VERSION 5.7 ;
  NOWIREEXTENSIONATPIN ON ;
  DIVIDERCHAR "/" ;
  BUSBITCHARS "[]" ;
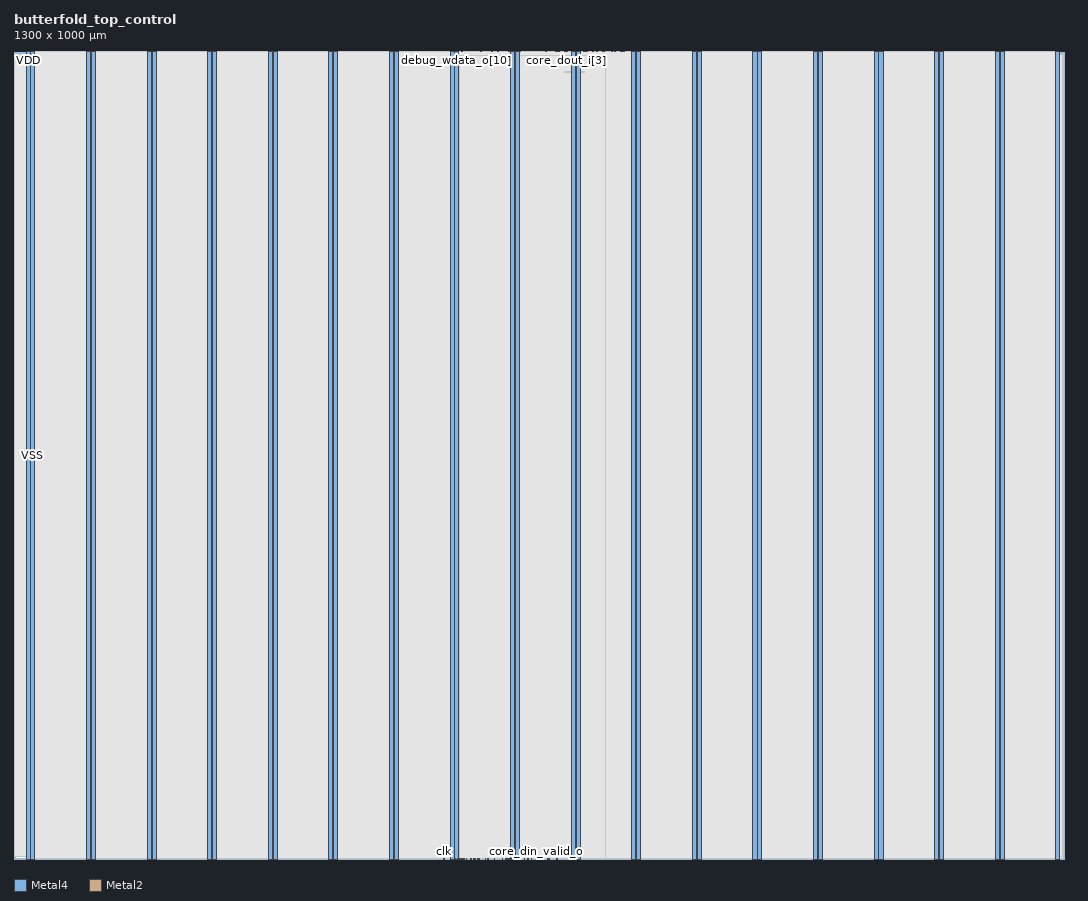
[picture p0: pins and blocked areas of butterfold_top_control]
MACRO butterfold_top_control
  CLASS BLOCK ;
  FOREIGN butterfold_top_control ;
  ORIGIN 0.000 0.000 ;
  SIZE 1300.000 BY 1000.000 ;
  PIN VDD
    DIRECTION INOUT ;
    USE POWER ;
    PORT
      LAYER Metal4 ;
        RECT 14.940 0.000 19.940 1000.000 ;
    END
    PORT
      LAYER Metal4 ;
        RECT 89.940 0.000 94.940 1000.000 ;
    END
    PORT
      LAYER Metal4 ;
        RECT 164.940 0.000 169.940 1000.000 ;
    END
    PORT
      LAYER Metal4 ;
        RECT 239.940 0.000 244.940 1000.000 ;
    END
    PORT
      LAYER Metal4 ;
        RECT 314.940 0.000 319.940 1000.000 ;
    END
    PORT
      LAYER Metal4 ;
        RECT 389.940 0.000 394.940 1000.000 ;
    END
    PORT
      LAYER Metal4 ;
        RECT 464.940 0.000 469.940 1000.000 ;
    END
    PORT
      LAYER Metal4 ;
        RECT 539.940 0.000 544.940 1000.000 ;
    END
    PORT
      LAYER Metal4 ;
        RECT 614.940 0.000 619.940 1000.000 ;
    END
    PORT
      LAYER Metal4 ;
        RECT 689.940 0.000 694.940 1000.000 ;
    END
    PORT
      LAYER Metal4 ;
        RECT 764.940 0.000 769.940 1000.000 ;
    END
    PORT
      LAYER Metal4 ;
        RECT 839.940 0.000 844.940 1000.000 ;
    END
    PORT
      LAYER Metal4 ;
        RECT 914.940 0.000 919.940 1000.000 ;
    END
    PORT
      LAYER Metal4 ;
        RECT 989.940 0.000 994.940 1000.000 ;
    END
    PORT
      LAYER Metal4 ;
        RECT 1064.940 0.000 1069.940 1000.000 ;
    END
    PORT
      LAYER Metal4 ;
        RECT 1139.940 0.000 1144.940 1000.000 ;
    END
    PORT
      LAYER Metal4 ;
        RECT 1214.940 0.000 1219.940 1000.000 ;
    END
    PORT
      LAYER Metal4 ;
        RECT 1289.940 0.000 1294.940 1000.000 ;
    END
  END VDD
  PIN VSS
    DIRECTION INOUT ;
    USE GROUND ;
    PORT
      LAYER Metal4 ;
        RECT 20.940 0.000 25.940 1000.000 ;
    END
    PORT
      LAYER Metal4 ;
        RECT 95.940 0.000 100.940 1000.000 ;
    END
    PORT
      LAYER Metal4 ;
        RECT 170.940 0.000 175.940 1000.000 ;
    END
    PORT
      LAYER Metal4 ;
        RECT 245.940 0.000 250.940 1000.000 ;
    END
    PORT
      LAYER Metal4 ;
        RECT 320.940 0.000 325.940 1000.000 ;
    END
    PORT
      LAYER Metal4 ;
        RECT 395.940 0.000 400.940 1000.000 ;
    END
    PORT
      LAYER Metal4 ;
        RECT 470.940 0.000 475.940 1000.000 ;
    END
    PORT
      LAYER Metal4 ;
        RECT 545.940 0.000 550.940 1000.000 ;
    END
    PORT
      LAYER Metal4 ;
        RECT 620.940 0.000 625.940 1000.000 ;
    END
    PORT
      LAYER Metal4 ;
        RECT 695.940 0.000 700.940 1000.000 ;
    END
    PORT
      LAYER Metal4 ;
        RECT 770.940 0.000 775.940 1000.000 ;
    END
    PORT
      LAYER Metal4 ;
        RECT 845.940 0.000 850.940 1000.000 ;
    END
    PORT
      LAYER Metal4 ;
        RECT 920.940 0.000 925.940 1000.000 ;
    END
    PORT
      LAYER Metal4 ;
        RECT 995.940 0.000 1000.940 1000.000 ;
    END
    PORT
      LAYER Metal4 ;
        RECT 1070.940 0.000 1075.940 1000.000 ;
    END
    PORT
      LAYER Metal4 ;
        RECT 1145.940 0.000 1150.940 1000.000 ;
    END
    PORT
      LAYER Metal4 ;
        RECT 1220.940 0.000 1225.940 1000.000 ;
    END
  END VSS
  PIN clk
    DIRECTION INPUT ;
    USE SIGNAL ;
    ANTENNAGATEAREA 4.738000 ;
    ANTENNADIFFAREA 0.410400 ;
    PORT
      LAYER Metal2 ;
        RECT 532.000 0.000 532.560 0.560 ;
    END
  END clk
  PIN core_din_ready_i
    DIRECTION INPUT ;
    USE SIGNAL ;
    ANTENNAGATEAREA 0.396000 ;
    ANTENNADIFFAREA 0.410400 ;
    PORT
      LAYER Metal2 ;
        RECT 633.920 999.440 634.480 1000.000 ;
    END
  END core_din_ready_i
  PIN core_din_valid_o
    DIRECTION OUTPUT ;
    USE SIGNAL ;
    ANTENNADIFFAREA 0.897600 ;
    PORT
      LAYER Metal2 ;
        RECT 646.240 0.000 646.800 0.560 ;
    END
  END core_din_valid_o
  PIN core_dout_i[0]
    DIRECTION INPUT ;
    USE SIGNAL ;
    ANTENNAGATEAREA 0.396000 ;
    ANTENNADIFFAREA 0.410400 ;
    PORT
      LAYER Metal2 ;
        RECT 695.520 999.440 696.080 1000.000 ;
    END
  END core_dout_i[0]
  PIN core_dout_i[1]
    DIRECTION INPUT ;
    USE SIGNAL ;
    ANTENNAGATEAREA 0.396000 ;
    ANTENNADIFFAREA 0.410400 ;
    PORT
      LAYER Metal2 ;
        RECT 715.680 999.440 716.240 1000.000 ;
    END
  END core_dout_i[1]
  PIN core_dout_i[2]
    DIRECTION INPUT ;
    USE SIGNAL ;
    ANTENNAGATEAREA 0.396000 ;
    ANTENNADIFFAREA 0.410400 ;
    PORT
      LAYER Metal2 ;
        RECT 722.400 999.440 722.960 1000.000 ;
    END
  END core_dout_i[2]
  PIN core_dout_i[3]
    DIRECTION INPUT ;
    USE SIGNAL ;
    ANTENNAGATEAREA 0.396000 ;
    ANTENNADIFFAREA 0.410400 ;
    PORT
      LAYER Metal2 ;
        RECT 684.320 999.440 684.880 1000.000 ;
    END
  END core_dout_i[3]
  PIN core_dout_i[4]
    DIRECTION INPUT ;
    USE SIGNAL ;
    ANTENNAGATEAREA 0.396000 ;
    ANTENNADIFFAREA 0.410400 ;
    PORT
      LAYER Metal2 ;
        RECT 670.880 999.440 671.440 1000.000 ;
    END
  END core_dout_i[4]
  PIN core_dout_i[5]
    DIRECTION INPUT ;
    USE SIGNAL ;
    ANTENNAGATEAREA 0.396000 ;
    ANTENNADIFFAREA 0.410400 ;
    PORT
      LAYER Metal2 ;
        RECT 710.080 999.440 710.640 1000.000 ;
    END
  END core_dout_i[5]
  PIN core_dout_i[6]
    DIRECTION INPUT ;
    USE SIGNAL ;
    ANTENNAGATEAREA 0.396000 ;
    ANTENNADIFFAREA 0.410400 ;
    PORT
      LAYER Metal2 ;
        RECT 679.840 999.440 680.400 1000.000 ;
    END
  END core_dout_i[6]
  PIN core_dout_i[7]
    DIRECTION INPUT ;
    USE SIGNAL ;
    ANTENNAGATEAREA 0.396000 ;
    ANTENNADIFFAREA 0.410400 ;
    PORT
      LAYER Metal2 ;
        RECT 724.640 999.440 725.200 1000.000 ;
    END
  END core_dout_i[7]
  PIN core_dout_valid_i
    DIRECTION INPUT ;
    USE SIGNAL ;
    ANTENNAGATEAREA 0.396000 ;
    ANTENNADIFFAREA 0.410400 ;
    PORT
      LAYER Metal2 ;
        RECT 705.600 999.440 706.160 1000.000 ;
    END
  END core_dout_valid_i
  PIN core_ofdm_active
    DIRECTION OUTPUT ;
    USE SIGNAL ;
    ANTENNADIFFAREA 0.897600 ;
    PORT
      LAYER Metal2 ;
        RECT 660.800 0.000 661.360 0.560 ;
    END
  END core_ofdm_active
  PIN core_result_ready_o
    DIRECTION OUTPUT ;
    USE SIGNAL ;
    ANTENNADIFFAREA 0.897600 ;
    PORT
      LAYER Metal2 ;
        RECT 610.400 0.000 610.960 0.560 ;
    END
  END core_result_ready_o
  PIN core_rx_complete
    DIRECTION OUTPUT ;
    USE SIGNAL ;
    ANTENNADIFFAREA 0.897600 ;
    PORT
      LAYER Metal2 ;
        RECT 614.880 0.000 615.440 0.560 ;
    END
  END core_rx_complete
  PIN core_rx_selected_complete
    DIRECTION OUTPUT ;
    USE SIGNAL ;
    ANTENNADIFFAREA 0.897600 ;
    PORT
      LAYER Metal2 ;
        RECT 617.120 0.000 617.680 0.560 ;
    END
  END core_rx_selected_complete
  PIN core_tx_complete
    DIRECTION OUTPUT ;
    USE SIGNAL ;
    ANTENNADIFFAREA 0.897600 ;
    PORT
      LAYER Metal2 ;
        RECT 611.520 0.000 612.080 0.560 ;
    END
  END core_tx_complete
  PIN debug_addr_o[0]
    DIRECTION OUTPUT ;
    USE SIGNAL ;
    ANTENNADIFFAREA 0.897600 ;
    PORT
      LAYER Metal2 ;
        RECT 604.800 0.000 605.360 0.560 ;
    END
  END debug_addr_o[0]
  PIN debug_addr_o[1]
    DIRECTION OUTPUT ;
    USE SIGNAL ;
    ANTENNADIFFAREA 0.897600 ;
    PORT
      LAYER Metal2 ;
        RECT 586.880 0.000 587.440 0.560 ;
    END
  END debug_addr_o[1]
  PIN debug_addr_o[2]
    DIRECTION OUTPUT ;
    USE SIGNAL ;
    ANTENNADIFFAREA 0.897600 ;
    PORT
      LAYER Metal2 ;
        RECT 551.040 0.000 551.600 0.560 ;
    END
  END debug_addr_o[2]
  PIN debug_addr_o[3]
    DIRECTION OUTPUT ;
    USE SIGNAL ;
    ANTENNADIFFAREA 0.897600 ;
    PORT
      LAYER Metal2 ;
        RECT 560.000 0.000 560.560 0.560 ;
    END
  END debug_addr_o[3]
  PIN debug_addr_o[4]
    DIRECTION OUTPUT ;
    USE SIGNAL ;
    ANTENNADIFFAREA 0.897600 ;
    PORT
      LAYER Metal2 ;
        RECT 548.800 0.000 549.360 0.560 ;
    END
  END debug_addr_o[4]
  PIN debug_addr_o[5]
    DIRECTION OUTPUT ;
    USE SIGNAL ;
    ANTENNADIFFAREA 0.897600 ;
    PORT
      LAYER Metal2 ;
        RECT 573.440 0.000 574.000 0.560 ;
    END
  END debug_addr_o[5]
  PIN debug_addr_o[6]
    DIRECTION OUTPUT ;
    USE SIGNAL ;
    ANTENNADIFFAREA 0.897600 ;
    PORT
      LAYER Metal2 ;
        RECT 570.080 0.000 570.640 0.560 ;
    END
  END debug_addr_o[6]
  PIN debug_addr_o[7]
    DIRECTION OUTPUT ;
    USE SIGNAL ;
    ANTENNADIFFAREA 0.897600 ;
    PORT
      LAYER Metal2 ;
        RECT 594.720 0.000 595.280 0.560 ;
    END
  END debug_addr_o[7]
  PIN debug_mode_o
    DIRECTION OUTPUT ;
    USE SIGNAL ;
    ANTENNADIFFAREA 0.897600 ;
    PORT
      LAYER Metal2 ;
        RECT 683.200 999.440 683.760 1000.000 ;
    END
  END debug_mode_o
  PIN debug_rdata_i[0]
    DIRECTION INPUT ;
    USE SIGNAL ;
    ANTENNAGATEAREA 0.396000 ;
    ANTENNADIFFAREA 0.410400 ;
    PORT
      LAYER Metal2 ;
        RECT 707.840 999.440 708.400 1000.000 ;
    END
  END debug_rdata_i[0]
  PIN debug_rdata_i[10]
    DIRECTION INPUT ;
    USE SIGNAL ;
    ANTENNAGATEAREA 0.396000 ;
    ANTENNADIFFAREA 0.410400 ;
    PORT
      LAYER Metal2 ;
        RECT 750.400 999.440 750.960 1000.000 ;
    END
  END debug_rdata_i[10]
  PIN debug_rdata_i[11]
    DIRECTION INPUT ;
    USE SIGNAL ;
    ANTENNAGATEAREA 0.396000 ;
    ANTENNADIFFAREA 0.410400 ;
    PORT
      LAYER Metal2 ;
        RECT 656.320 999.440 656.880 1000.000 ;
    END
  END debug_rdata_i[11]
  PIN debug_rdata_i[12]
    DIRECTION INPUT ;
    USE SIGNAL ;
    ANTENNAGATEAREA 0.396000 ;
    ANTENNADIFFAREA 0.410400 ;
    PORT
      LAYER Metal2 ;
        RECT 657.440 999.440 658.000 1000.000 ;
    END
  END debug_rdata_i[12]
  PIN debug_rdata_i[13]
    DIRECTION INPUT ;
    USE SIGNAL ;
    ANTENNAGATEAREA 0.396000 ;
    ANTENNADIFFAREA 0.410400 ;
    PORT
      LAYER Metal2 ;
        RECT 658.560 999.440 659.120 1000.000 ;
    END
  END debug_rdata_i[13]
  PIN debug_rdata_i[14]
    DIRECTION INPUT ;
    USE SIGNAL ;
    ANTENNAGATEAREA 0.396000 ;
    ANTENNADIFFAREA 0.410400 ;
    PORT
      LAYER Metal2 ;
        RECT 743.680 999.440 744.240 1000.000 ;
    END
  END debug_rdata_i[14]
  PIN debug_rdata_i[15]
    DIRECTION INPUT ;
    USE SIGNAL ;
    ANTENNAGATEAREA 0.396000 ;
    ANTENNADIFFAREA 0.410400 ;
    PORT
      LAYER Metal2 ;
        RECT 751.520 999.440 752.080 1000.000 ;
    END
  END debug_rdata_i[15]
  PIN debug_rdata_i[1]
    DIRECTION INPUT ;
    USE SIGNAL ;
    ANTENNAGATEAREA 0.396000 ;
    ANTENNADIFFAREA 0.410400 ;
    PORT
      LAYER Metal2 ;
        RECT 739.200 999.440 739.760 1000.000 ;
    END
  END debug_rdata_i[1]
  PIN debug_rdata_i[2]
    DIRECTION INPUT ;
    USE SIGNAL ;
    ANTENNAGATEAREA 0.396000 ;
    ANTENNADIFFAREA 0.410400 ;
    PORT
      LAYER Metal2 ;
        RECT 752.640 999.440 753.200 1000.000 ;
    END
  END debug_rdata_i[2]
  PIN debug_rdata_i[3]
    DIRECTION INPUT ;
    USE SIGNAL ;
    ANTENNAGATEAREA 0.396000 ;
    ANTENNADIFFAREA 0.410400 ;
    PORT
      LAYER Metal2 ;
        RECT 667.520 999.440 668.080 1000.000 ;
    END
  END debug_rdata_i[3]
  PIN debug_rdata_i[4]
    DIRECTION INPUT ;
    USE SIGNAL ;
    ANTENNAGATEAREA 0.396000 ;
    ANTENNADIFFAREA 0.410400 ;
    PORT
      LAYER Metal2 ;
        RECT 673.120 999.440 673.680 1000.000 ;
    END
  END debug_rdata_i[4]
  PIN debug_rdata_i[5]
    DIRECTION INPUT ;
    USE SIGNAL ;
    ANTENNAGATEAREA 0.396000 ;
    ANTENNADIFFAREA 0.410400 ;
    PORT
      LAYER Metal2 ;
        RECT 740.320 999.440 740.880 1000.000 ;
    END
  END debug_rdata_i[5]
  PIN debug_rdata_i[6]
    DIRECTION INPUT ;
    USE SIGNAL ;
    ANTENNAGATEAREA 0.396000 ;
    ANTENNADIFFAREA 0.410400 ;
    PORT
      LAYER Metal2 ;
        RECT 754.880 999.440 755.440 1000.000 ;
    END
  END debug_rdata_i[6]
  PIN debug_rdata_i[7]
    DIRECTION INPUT ;
    USE SIGNAL ;
    ANTENNAGATEAREA 0.396000 ;
    ANTENNADIFFAREA 0.410400 ;
    PORT
      LAYER Metal2 ;
        RECT 723.520 999.440 724.080 1000.000 ;
    END
  END debug_rdata_i[7]
  PIN debug_rdata_i[8]
    DIRECTION INPUT ;
    USE SIGNAL ;
    ANTENNAGATEAREA 0.396000 ;
    ANTENNADIFFAREA 0.410400 ;
    PORT
      LAYER Metal2 ;
        RECT 692.160 999.440 692.720 1000.000 ;
    END
  END debug_rdata_i[8]
  PIN debug_rdata_i[9]
    DIRECTION INPUT ;
    USE SIGNAL ;
    ANTENNAGATEAREA 0.396000 ;
    ANTENNADIFFAREA 0.410400 ;
    PORT
      LAYER Metal2 ;
        RECT 706.720 999.440 707.280 1000.000 ;
    END
  END debug_rdata_i[9]
  PIN debug_ready_i
    DIRECTION INPUT ;
    USE SIGNAL ;
    ANTENNAGATEAREA 0.396000 ;
    ANTENNADIFFAREA 0.410400 ;
    PORT
      LAYER Metal2 ;
        RECT 686.560 999.440 687.120 1000.000 ;
    END
  END debug_ready_i
  PIN debug_req_o
    DIRECTION OUTPUT ;
    USE SIGNAL ;
    ANTENNADIFFAREA 0.897600 ;
    PORT
      LAYER Metal2 ;
        RECT 680.960 999.440 681.520 1000.000 ;
    END
  END debug_req_o
  PIN debug_rvalid_i
    DIRECTION INPUT ;
    USE SIGNAL ;
    ANTENNAGATEAREA 0.396000 ;
    ANTENNADIFFAREA 0.410400 ;
    PORT
      LAYER Metal2 ;
        RECT 682.080 999.440 682.640 1000.000 ;
    END
  END debug_rvalid_i
  PIN debug_wdata_o[0]
    DIRECTION OUTPUT ;
    USE SIGNAL ;
    ANTENNADIFFAREA 0.897600 ;
    PORT
      LAYER Metal2 ;
        RECT 626.080 999.440 626.640 1000.000 ;
    END
  END debug_wdata_o[0]
  PIN debug_wdata_o[10]
    DIRECTION OUTPUT ;
    USE SIGNAL ;
    ANTENNADIFFAREA 0.897600 ;
    PORT
      LAYER Metal2 ;
        RECT 547.680 999.440 548.240 1000.000 ;
    END
  END debug_wdata_o[10]
  PIN debug_wdata_o[11]
    DIRECTION OUTPUT ;
    USE SIGNAL ;
    ANTENNADIFFAREA 0.897600 ;
    PORT
      LAYER Metal2 ;
        RECT 551.040 999.440 551.600 1000.000 ;
    END
  END debug_wdata_o[11]
  PIN debug_wdata_o[12]
    DIRECTION OUTPUT ;
    USE SIGNAL ;
    ANTENNADIFFAREA 0.897600 ;
    PORT
      LAYER Metal2 ;
        RECT 549.920 999.440 550.480 1000.000 ;
    END
  END debug_wdata_o[12]
  PIN debug_wdata_o[13]
    DIRECTION OUTPUT ;
    USE SIGNAL ;
    ANTENNADIFFAREA 0.897600 ;
    PORT
      LAYER Metal2 ;
        RECT 574.560 999.440 575.120 1000.000 ;
    END
  END debug_wdata_o[13]
  PIN debug_wdata_o[14]
    DIRECTION OUTPUT ;
    USE SIGNAL ;
    ANTENNADIFFAREA 0.897600 ;
    PORT
      LAYER Metal2 ;
        RECT 593.600 999.440 594.160 1000.000 ;
    END
  END debug_wdata_o[14]
  PIN debug_wdata_o[15]
    DIRECTION OUTPUT ;
    USE SIGNAL ;
    ANTENNADIFFAREA 0.897600 ;
    PORT
      LAYER Metal2 ;
        RECT 591.360 999.440 591.920 1000.000 ;
    END
  END debug_wdata_o[15]
  PIN debug_wdata_o[1]
    DIRECTION OUTPUT ;
    USE SIGNAL ;
    ANTENNADIFFAREA 0.897600 ;
    PORT
      LAYER Metal2 ;
        RECT 617.120 999.440 617.680 1000.000 ;
    END
  END debug_wdata_o[1]
  PIN debug_wdata_o[2]
    DIRECTION OUTPUT ;
    USE SIGNAL ;
    ANTENNADIFFAREA 0.897600 ;
    PORT
      LAYER Metal2 ;
        RECT 549.920 0.000 550.480 0.560 ;
    END
  END debug_wdata_o[2]
  PIN debug_wdata_o[3]
    DIRECTION OUTPUT ;
    USE SIGNAL ;
    ANTENNADIFFAREA 0.897600 ;
    PORT
      LAYER Metal2 ;
        RECT 577.920 999.440 578.480 1000.000 ;
    END
  END debug_wdata_o[3]
  PIN debug_wdata_o[4]
    DIRECTION OUTPUT ;
    USE SIGNAL ;
    ANTENNADIFFAREA 0.897600 ;
    PORT
      LAYER Metal2 ;
        RECT 554.400 999.440 554.960 1000.000 ;
    END
  END debug_wdata_o[4]
  PIN debug_wdata_o[5]
    DIRECTION OUTPUT ;
    USE SIGNAL ;
    ANTENNADIFFAREA 0.897600 ;
    PORT
      LAYER Metal2 ;
        RECT 572.320 999.440 572.880 1000.000 ;
    END
  END debug_wdata_o[5]
  PIN debug_wdata_o[6]
    DIRECTION OUTPUT ;
    USE SIGNAL ;
    ANTENNADIFFAREA 0.897600 ;
    PORT
      LAYER Metal2 ;
        RECT 571.200 0.000 571.760 0.560 ;
    END
  END debug_wdata_o[6]
  PIN debug_wdata_o[7]
    DIRECTION OUTPUT ;
    USE SIGNAL ;
    ANTENNADIFFAREA 0.897600 ;
    PORT
      LAYER Metal2 ;
        RECT 612.640 999.440 613.200 1000.000 ;
    END
  END debug_wdata_o[7]
  PIN debug_wdata_o[8]
    DIRECTION OUTPUT ;
    USE SIGNAL ;
    ANTENNADIFFAREA 0.897600 ;
    PORT
      LAYER Metal2 ;
        RECT 616.000 999.440 616.560 1000.000 ;
    END
  END debug_wdata_o[8]
  PIN debug_wdata_o[9]
    DIRECTION OUTPUT ;
    USE SIGNAL ;
    ANTENNADIFFAREA 0.897600 ;
    PORT
      LAYER Metal2 ;
        RECT 599.200 999.440 599.760 1000.000 ;
    END
  END debug_wdata_o[9]
  PIN debug_write_o
    DIRECTION OUTPUT ;
    USE SIGNAL ;
    ANTENNADIFFAREA 0.897600 ;
    PORT
      LAYER Metal2 ;
        RECT 672.000 999.440 672.560 1000.000 ;
    END
  END debug_write_o
  PIN din[0]
    DIRECTION INPUT ;
    USE SIGNAL ;
    ANTENNAGATEAREA 0.396000 ;
    ANTENNADIFFAREA 0.410400 ;
    PORT
      LAYER Metal2 ;
        RECT 651.840 0.000 652.400 0.560 ;
    END
  END din[0]
  PIN din[1]
    DIRECTION INPUT ;
    USE SIGNAL ;
    ANTENNAGATEAREA 0.396000 ;
    ANTENNADIFFAREA 0.410400 ;
    PORT
      LAYER Metal2 ;
        RECT 621.600 0.000 622.160 0.560 ;
    END
  END din[1]
  PIN din[2]
    DIRECTION INPUT ;
    USE SIGNAL ;
    ANTENNAGATEAREA 0.726000 ;
    ANTENNADIFFAREA 0.410400 ;
    PORT
      LAYER Metal2 ;
        RECT 553.280 0.000 553.840 0.560 ;
    END
  END din[2]
  PIN din[3]
    DIRECTION INPUT ;
    USE SIGNAL ;
    ANTENNAGATEAREA 0.396000 ;
    ANTENNADIFFAREA 0.410400 ;
    PORT
      LAYER Metal2 ;
        RECT 636.160 0.000 636.720 0.560 ;
    END
  END din[3]
  PIN din[4]
    DIRECTION INPUT ;
    USE SIGNAL ;
    ANTENNAGATEAREA 0.726000 ;
    ANTENNADIFFAREA 0.410400 ;
    PORT
      LAYER Metal2 ;
        RECT 552.160 0.000 552.720 0.560 ;
    END
  END din[4]
  PIN din[5]
    DIRECTION INPUT ;
    USE SIGNAL ;
    ANTENNAGATEAREA 0.726000 ;
    ANTENNADIFFAREA 0.410400 ;
    PORT
      LAYER Metal2 ;
        RECT 574.560 0.000 575.120 0.560 ;
    END
  END din[5]
  PIN din[6]
    DIRECTION INPUT ;
    USE SIGNAL ;
    ANTENNAGATEAREA 0.396000 ;
    ANTENNADIFFAREA 0.410400 ;
    PORT
      LAYER Metal2 ;
        RECT 613.760 0.000 614.320 0.560 ;
    END
  END din[6]
  PIN din[7]
    DIRECTION INPUT ;
    USE SIGNAL ;
    ANTENNAGATEAREA 0.396000 ;
    ANTENNADIFFAREA 0.410400 ;
    PORT
      LAYER Metal2 ;
        RECT 631.680 0.000 632.240 0.560 ;
    END
  END din[7]
  PIN din_ready_o
    DIRECTION OUTPUT ;
    USE SIGNAL ;
    ANTENNADIFFAREA 0.897600 ;
    PORT
      LAYER Metal2 ;
        RECT 632.800 999.440 633.360 1000.000 ;
    END
  END din_ready_o
  PIN din_valid_i
    DIRECTION INPUT ;
    USE SIGNAL ;
    ANTENNAGATEAREA 0.396000 ;
    ANTENNADIFFAREA 0.410400 ;
    PORT
      LAYER Metal2 ;
        RECT 640.640 0.000 641.200 0.560 ;
    END
  END din_valid_i
  PIN dout[0]
    DIRECTION OUTPUT ;
    USE SIGNAL ;
    ANTENNADIFFAREA 0.897600 ;
    PORT
      LAYER Metal2 ;
        RECT 694.400 999.440 694.960 1000.000 ;
    END
  END dout[0]
  PIN dout[1]
    DIRECTION OUTPUT ;
    USE SIGNAL ;
    ANTENNADIFFAREA 0.897600 ;
    PORT
      LAYER Metal2 ;
        RECT 714.560 999.440 715.120 1000.000 ;
    END
  END dout[1]
  PIN dout[2]
    DIRECTION OUTPUT ;
    USE SIGNAL ;
    ANTENNADIFFAREA 0.897600 ;
    PORT
      LAYER Metal2 ;
        RECT 725.760 999.440 726.320 1000.000 ;
    END
  END dout[2]
  PIN dout[3]
    DIRECTION OUTPUT ;
    USE SIGNAL ;
    ANTENNADIFFAREA 0.897600 ;
    PORT
      LAYER Metal2 ;
        RECT 688.800 999.440 689.360 1000.000 ;
    END
  END dout[3]
  PIN dout[4]
    DIRECTION OUTPUT ;
    USE SIGNAL ;
    ANTENNADIFFAREA 0.897600 ;
    PORT
      LAYER Metal2 ;
        RECT 675.360 999.440 675.920 1000.000 ;
    END
  END dout[4]
  PIN dout[5]
    DIRECTION OUTPUT ;
    USE SIGNAL ;
    ANTENNADIFFAREA 0.897600 ;
    PORT
      LAYER Metal2 ;
        RECT 711.200 999.440 711.760 1000.000 ;
    END
  END dout[5]
  PIN dout[6]
    DIRECTION OUTPUT ;
    USE SIGNAL ;
    ANTENNADIFFAREA 0.897600 ;
    PORT
      LAYER Metal2 ;
        RECT 678.720 999.440 679.280 1000.000 ;
    END
  END dout[6]
  PIN dout[7]
    DIRECTION OUTPUT ;
    USE SIGNAL ;
    ANTENNADIFFAREA 0.897600 ;
    PORT
      LAYER Metal2 ;
        RECT 728.000 999.440 728.560 1000.000 ;
    END
  END dout[7]
  PIN dout_valid_o
    DIRECTION OUTPUT ;
    USE SIGNAL ;
    ANTENNADIFFAREA 0.897600 ;
    PORT
      LAYER Metal2 ;
        RECT 730.240 999.440 730.800 1000.000 ;
    END
  END dout_valid_o
  PIN drain_active
    DIRECTION OUTPUT ;
    USE SIGNAL ;
    ANTENNADIFFAREA 0.897600 ;
    PORT
      LAYER Metal2 ;
        RECT 663.040 0.000 663.600 0.560 ;
    END
  END drain_active
  PIN ext_state[0]
    DIRECTION OUTPUT ;
    USE SIGNAL ;
    ANTENNADIFFAREA 0.897600 ;
    PORT
      LAYER Metal2 ;
        RECT 623.840 0.000 624.400 0.560 ;
    END
  END ext_state[0]
  PIN ext_state[1]
    DIRECTION OUTPUT ;
    USE SIGNAL ;
    ANTENNADIFFAREA 0.897600 ;
    PORT
      LAYER Metal2 ;
        RECT 620.480 0.000 621.040 0.560 ;
    END
  END ext_state[1]
  PIN ext_state[2]
    DIRECTION OUTPUT ;
    USE SIGNAL ;
    ANTENNADIFFAREA 0.360800 ;
    PORT
      LAYER Metal2 ;
        RECT 716.800 999.440 717.360 1000.000 ;
    END
  END ext_state[2]
  PIN external_fire
    DIRECTION OUTPUT ;
    USE SIGNAL ;
    ANTENNADIFFAREA 0.897600 ;
    PORT
      LAYER Metal2 ;
        RECT 618.240 0.000 618.800 0.560 ;
    END
  END external_fire
  PIN feeder_start
    DIRECTION OUTPUT ;
    USE SIGNAL ;
    ANTENNADIFFAREA 0.897600 ;
    PORT
      LAYER Metal2 ;
        RECT 672.000 0.000 672.560 0.560 ;
    END
  END feeder_start
  PIN job_head_command[0]
    DIRECTION OUTPUT ;
    USE SIGNAL ;
    ANTENNADIFFAREA 0.897600 ;
    PORT
      LAYER Metal2 ;
        RECT 612.640 0.000 613.200 0.560 ;
    END
  END job_head_command[0]
  PIN job_head_command[1]
    DIRECTION OUTPUT ;
    USE SIGNAL ;
    ANTENNADIFFAREA 0.897600 ;
    PORT
      LAYER Metal2 ;
        RECT 583.520 0.000 584.080 0.560 ;
    END
  END job_head_command[1]
  PIN job_head_command[2]
    DIRECTION OUTPUT ;
    USE SIGNAL ;
    ANTENNADIFFAREA 0.897600 ;
    PORT
      LAYER Metal2 ;
        RECT 565.600 0.000 566.160 0.560 ;
    END
  END job_head_command[2]
  PIN job_head_command[3]
    DIRECTION OUTPUT ;
    USE SIGNAL ;
    ANTENNADIFFAREA 0.897600 ;
    PORT
      LAYER Metal2 ;
        RECT 556.640 0.000 557.200 0.560 ;
    END
  END job_head_command[3]
  PIN job_head_command[4]
    DIRECTION OUTPUT ;
    USE SIGNAL ;
    ANTENNADIFFAREA 0.897600 ;
    PORT
      LAYER Metal2 ;
        RECT 554.400 0.000 554.960 0.560 ;
    END
  END job_head_command[4]
  PIN job_head_command[5]
    DIRECTION OUTPUT ;
    USE SIGNAL ;
    ANTENNADIFFAREA 0.897600 ;
    PORT
      LAYER Metal2 ;
        RECT 575.680 0.000 576.240 0.560 ;
    END
  END job_head_command[5]
  PIN job_head_command[6]
    DIRECTION OUTPUT ;
    USE SIGNAL ;
    ANTENNADIFFAREA 0.897600 ;
    PORT
      LAYER Metal2 ;
        RECT 568.960 0.000 569.520 0.560 ;
    END
  END job_head_command[6]
  PIN job_head_command[7]
    DIRECTION OUTPUT ;
    USE SIGNAL ;
    ANTENNADIFFAREA 0.897600 ;
    PORT
      LAYER Metal2 ;
        RECT 585.760 0.000 586.320 0.560 ;
    END
  END job_head_command[7]
  PIN job_push
    DIRECTION OUTPUT ;
    USE SIGNAL ;
    ANTENNADIFFAREA 0.897600 ;
    PORT
      LAYER Metal2 ;
        RECT 688.800 0.000 689.360 0.560 ;
    END
  END job_push
  PIN rst_n
    DIRECTION INPUT ;
    USE SIGNAL ;
    ANTENNAGATEAREA 0.396000 ;
    ANTENNADIFFAREA 0.410400 ;
    PORT
      LAYER Metal2 ;
        RECT 545.440 0.000 546.000 0.560 ;
    END
  END rst_n
  PIN serializer_dout_i[0]
    DIRECTION INPUT ;
    USE SIGNAL ;
    ANTENNAGATEAREA 0.396000 ;
    ANTENNADIFFAREA 0.410400 ;
    PORT
      LAYER Metal2 ;
        RECT 693.280 999.440 693.840 1000.000 ;
    END
  END serializer_dout_i[0]
  PIN serializer_dout_i[1]
    DIRECTION INPUT ;
    USE SIGNAL ;
    ANTENNAGATEAREA 0.396000 ;
    ANTENNADIFFAREA 0.410400 ;
    PORT
      LAYER Metal2 ;
        RECT 713.440 999.440 714.000 1000.000 ;
    END
  END serializer_dout_i[1]
  PIN serializer_dout_i[2]
    DIRECTION INPUT ;
    USE SIGNAL ;
    ANTENNAGATEAREA 0.396000 ;
    ANTENNADIFFAREA 0.410400 ;
    PORT
      LAYER Metal2 ;
        RECT 726.880 999.440 727.440 1000.000 ;
    END
  END serializer_dout_i[2]
  PIN serializer_dout_i[3]
    DIRECTION INPUT ;
    USE SIGNAL ;
    ANTENNAGATEAREA 0.396000 ;
    ANTENNADIFFAREA 0.410400 ;
    PORT
      LAYER Metal2 ;
        RECT 687.680 999.440 688.240 1000.000 ;
    END
  END serializer_dout_i[3]
  PIN serializer_dout_i[4]
    DIRECTION INPUT ;
    USE SIGNAL ;
    ANTENNAGATEAREA 0.396000 ;
    ANTENNADIFFAREA 0.410400 ;
    PORT
      LAYER Metal2 ;
        RECT 674.240 999.440 674.800 1000.000 ;
    END
  END serializer_dout_i[4]
  PIN serializer_dout_i[5]
    DIRECTION INPUT ;
    USE SIGNAL ;
    ANTENNAGATEAREA 0.396000 ;
    ANTENNADIFFAREA 0.410400 ;
    PORT
      LAYER Metal2 ;
        RECT 712.320 999.440 712.880 1000.000 ;
    END
  END serializer_dout_i[5]
  PIN serializer_dout_i[6]
    DIRECTION INPUT ;
    USE SIGNAL ;
    ANTENNAGATEAREA 0.396000 ;
    ANTENNADIFFAREA 0.410400 ;
    PORT
      LAYER Metal2 ;
        RECT 676.480 999.440 677.040 1000.000 ;
    END
  END serializer_dout_i[6]
  PIN serializer_dout_i[7]
    DIRECTION INPUT ;
    USE SIGNAL ;
    ANTENNAGATEAREA 0.396000 ;
    ANTENNADIFFAREA 0.410400 ;
    PORT
      LAYER Metal2 ;
        RECT 729.120 999.440 729.680 1000.000 ;
    END
  END serializer_dout_i[7]
  PIN serializer_job_done_i
    DIRECTION INPUT ;
    USE SIGNAL ;
    ANTENNAGATEAREA 0.396000 ;
    ANTENNADIFFAREA 0.410400 ;
    PORT
      LAYER Metal2 ;
        RECT 616.000 0.000 616.560 0.560 ;
    END
  END serializer_job_done_i
  PIN serializer_ready_i
    DIRECTION INPUT ;
    USE SIGNAL ;
    ANTENNAGATEAREA 0.396000 ;
    ANTENNADIFFAREA 0.410400 ;
    PORT
      LAYER Metal2 ;
        RECT 608.160 0.000 608.720 0.560 ;
    END
  END serializer_ready_i
  PIN serializer_valid_i
    DIRECTION INPUT ;
    USE SIGNAL ;
    ANTENNAGATEAREA 0.396000 ;
    ANTENNADIFFAREA 0.410400 ;
    PORT
      LAYER Metal2 ;
        RECT 721.280 999.440 721.840 1000.000 ;
    END
  END serializer_valid_i
  PIN standalone_active_o
    DIRECTION OUTPUT ;
    USE SIGNAL ;
    ANTENNADIFFAREA 0.897600 ;
    PORT
      LAYER Metal2 ;
        RECT 609.280 0.000 609.840 0.560 ;
    END
  END standalone_active_o
  PIN top_state_o[0]
    DIRECTION OUTPUT ;
    USE SIGNAL ;
    ANTENNADIFFAREA 0.897600 ;
    PORT
      LAYER Metal2 ;
        RECT 738.080 999.440 738.640 1000.000 ;
    END
  END top_state_o[0]
  PIN top_state_o[1]
    DIRECTION OUTPUT ;
    USE SIGNAL ;
    ANTENNADIFFAREA 0.897600 ;
    PORT
      LAYER Metal2 ;
        RECT 622.720 0.000 623.280 0.560 ;
    END
  END top_state_o[1]
  PIN top_state_o[2]
    DIRECTION OUTPUT ;
    USE SIGNAL ;
    ANTENNADIFFAREA 0.897600 ;
    PORT
      LAYER Metal2 ;
        RECT 708.960 999.440 709.520 1000.000 ;
    END
  END top_state_o[2]
  PIN top_state_o[3]
    DIRECTION OUTPUT ;
    USE SIGNAL ;
    ANTENNADIFFAREA 0.897600 ;
    PORT
      LAYER Metal2 ;
        RECT 701.120 999.440 701.680 1000.000 ;
    END
  END top_state_o[3]
  PIN top_state_o[4]
    DIRECTION OUTPUT ;
    USE SIGNAL ;
    ANTENNADIFFAREA 0.897600 ;
    PORT
      LAYER Metal2 ;
        RECT 619.360 0.000 619.920 0.560 ;
    END
  END top_state_o[4]
  OBS
      LAYER Nwell ;
        RECT 0.690 993.520 1299.070 996.110 ;
      LAYER Pwell ;
        RECT 0.690 990.000 1299.070 993.520 ;
      LAYER Nwell ;
        RECT 0.690 985.680 1299.070 990.000 ;
      LAYER Pwell ;
        RECT 0.690 982.160 1299.070 985.680 ;
      LAYER Nwell ;
        RECT 0.690 977.840 1299.070 982.160 ;
      LAYER Pwell ;
        RECT 0.690 974.320 1299.070 977.840 ;
      LAYER Nwell ;
        RECT 0.690 970.000 1299.070 974.320 ;
      LAYER Pwell ;
        RECT 0.690 966.480 1299.070 970.000 ;
      LAYER Nwell ;
        RECT 0.690 962.160 1299.070 966.480 ;
      LAYER Pwell ;
        RECT 0.690 958.640 1299.070 962.160 ;
      LAYER Nwell ;
        RECT 0.690 954.320 1299.070 958.640 ;
      LAYER Pwell ;
        RECT 0.690 950.800 1299.070 954.320 ;
      LAYER Nwell ;
        RECT 0.690 946.480 1299.070 950.800 ;
      LAYER Pwell ;
        RECT 0.690 942.960 1299.070 946.480 ;
      LAYER Nwell ;
        RECT 0.690 938.640 1299.070 942.960 ;
      LAYER Pwell ;
        RECT 0.690 935.120 1299.070 938.640 ;
      LAYER Nwell ;
        RECT 0.690 930.800 1299.070 935.120 ;
      LAYER Pwell ;
        RECT 0.690 927.280 1299.070 930.800 ;
      LAYER Nwell ;
        RECT 0.690 922.960 1299.070 927.280 ;
      LAYER Pwell ;
        RECT 0.690 919.440 1299.070 922.960 ;
      LAYER Nwell ;
        RECT 0.690 915.120 1299.070 919.440 ;
      LAYER Pwell ;
        RECT 0.690 911.600 1299.070 915.120 ;
      LAYER Nwell ;
        RECT 0.690 907.280 1299.070 911.600 ;
      LAYER Pwell ;
        RECT 0.690 903.760 1299.070 907.280 ;
      LAYER Nwell ;
        RECT 0.690 899.440 1299.070 903.760 ;
      LAYER Pwell ;
        RECT 0.690 895.920 1299.070 899.440 ;
      LAYER Nwell ;
        RECT 0.690 891.600 1299.070 895.920 ;
      LAYER Pwell ;
        RECT 0.690 888.080 1299.070 891.600 ;
      LAYER Nwell ;
        RECT 0.690 883.760 1299.070 888.080 ;
      LAYER Pwell ;
        RECT 0.690 880.240 1299.070 883.760 ;
      LAYER Nwell ;
        RECT 0.690 875.920 1299.070 880.240 ;
      LAYER Pwell ;
        RECT 0.690 872.400 1299.070 875.920 ;
      LAYER Nwell ;
        RECT 0.690 868.080 1299.070 872.400 ;
      LAYER Pwell ;
        RECT 0.690 864.560 1299.070 868.080 ;
      LAYER Nwell ;
        RECT 0.690 860.240 1299.070 864.560 ;
      LAYER Pwell ;
        RECT 0.690 856.720 1299.070 860.240 ;
      LAYER Nwell ;
        RECT 0.690 852.400 1299.070 856.720 ;
      LAYER Pwell ;
        RECT 0.690 848.880 1299.070 852.400 ;
      LAYER Nwell ;
        RECT 0.690 844.560 1299.070 848.880 ;
      LAYER Pwell ;
        RECT 0.690 841.040 1299.070 844.560 ;
      LAYER Nwell ;
        RECT 0.690 836.720 1299.070 841.040 ;
      LAYER Pwell ;
        RECT 0.690 833.200 1299.070 836.720 ;
      LAYER Nwell ;
        RECT 0.690 828.880 1299.070 833.200 ;
      LAYER Pwell ;
        RECT 0.690 825.360 1299.070 828.880 ;
      LAYER Nwell ;
        RECT 0.690 821.040 1299.070 825.360 ;
      LAYER Pwell ;
        RECT 0.690 817.520 1299.070 821.040 ;
      LAYER Nwell ;
        RECT 0.690 813.200 1299.070 817.520 ;
      LAYER Pwell ;
        RECT 0.690 809.680 1299.070 813.200 ;
      LAYER Nwell ;
        RECT 0.690 805.360 1299.070 809.680 ;
      LAYER Pwell ;
        RECT 0.690 801.840 1299.070 805.360 ;
      LAYER Nwell ;
        RECT 0.690 797.520 1299.070 801.840 ;
      LAYER Pwell ;
        RECT 0.690 794.000 1299.070 797.520 ;
      LAYER Nwell ;
        RECT 0.690 789.680 1299.070 794.000 ;
      LAYER Pwell ;
        RECT 0.690 786.160 1299.070 789.680 ;
      LAYER Nwell ;
        RECT 0.690 781.840 1299.070 786.160 ;
      LAYER Pwell ;
        RECT 0.690 778.320 1299.070 781.840 ;
      LAYER Nwell ;
        RECT 0.690 774.000 1299.070 778.320 ;
      LAYER Pwell ;
        RECT 0.690 770.480 1299.070 774.000 ;
      LAYER Nwell ;
        RECT 0.690 766.160 1299.070 770.480 ;
      LAYER Pwell ;
        RECT 0.690 762.640 1299.070 766.160 ;
      LAYER Nwell ;
        RECT 0.690 758.320 1299.070 762.640 ;
      LAYER Pwell ;
        RECT 0.690 754.800 1299.070 758.320 ;
      LAYER Nwell ;
        RECT 0.690 750.480 1299.070 754.800 ;
      LAYER Pwell ;
        RECT 0.690 746.960 1299.070 750.480 ;
      LAYER Nwell ;
        RECT 0.690 742.640 1299.070 746.960 ;
      LAYER Pwell ;
        RECT 0.690 739.120 1299.070 742.640 ;
      LAYER Nwell ;
        RECT 0.690 734.800 1299.070 739.120 ;
      LAYER Pwell ;
        RECT 0.690 731.280 1299.070 734.800 ;
      LAYER Nwell ;
        RECT 0.690 726.960 1299.070 731.280 ;
      LAYER Pwell ;
        RECT 0.690 723.440 1299.070 726.960 ;
      LAYER Nwell ;
        RECT 0.690 719.120 1299.070 723.440 ;
      LAYER Pwell ;
        RECT 0.690 715.600 1299.070 719.120 ;
      LAYER Nwell ;
        RECT 0.690 711.280 1299.070 715.600 ;
      LAYER Pwell ;
        RECT 0.690 707.760 1299.070 711.280 ;
      LAYER Nwell ;
        RECT 0.690 703.440 1299.070 707.760 ;
      LAYER Pwell ;
        RECT 0.690 699.920 1299.070 703.440 ;
      LAYER Nwell ;
        RECT 0.690 695.600 1299.070 699.920 ;
      LAYER Pwell ;
        RECT 0.690 692.080 1299.070 695.600 ;
      LAYER Nwell ;
        RECT 0.690 687.760 1299.070 692.080 ;
      LAYER Pwell ;
        RECT 0.690 684.240 1299.070 687.760 ;
      LAYER Nwell ;
        RECT 0.690 679.920 1299.070 684.240 ;
      LAYER Pwell ;
        RECT 0.690 676.400 1299.070 679.920 ;
      LAYER Nwell ;
        RECT 0.690 672.080 1299.070 676.400 ;
      LAYER Pwell ;
        RECT 0.690 668.560 1299.070 672.080 ;
      LAYER Nwell ;
        RECT 0.690 664.240 1299.070 668.560 ;
      LAYER Pwell ;
        RECT 0.690 660.720 1299.070 664.240 ;
      LAYER Nwell ;
        RECT 0.690 656.400 1299.070 660.720 ;
      LAYER Pwell ;
        RECT 0.690 652.880 1299.070 656.400 ;
      LAYER Nwell ;
        RECT 0.690 648.560 1299.070 652.880 ;
      LAYER Pwell ;
        RECT 0.690 645.040 1299.070 648.560 ;
      LAYER Nwell ;
        RECT 0.690 640.720 1299.070 645.040 ;
      LAYER Pwell ;
        RECT 0.690 637.200 1299.070 640.720 ;
      LAYER Nwell ;
        RECT 0.690 632.880 1299.070 637.200 ;
      LAYER Pwell ;
        RECT 0.690 629.360 1299.070 632.880 ;
      LAYER Nwell ;
        RECT 0.690 625.040 1299.070 629.360 ;
      LAYER Pwell ;
        RECT 0.690 621.520 1299.070 625.040 ;
      LAYER Nwell ;
        RECT 0.690 617.200 1299.070 621.520 ;
      LAYER Pwell ;
        RECT 0.690 613.680 1299.070 617.200 ;
      LAYER Nwell ;
        RECT 0.690 609.360 1299.070 613.680 ;
      LAYER Pwell ;
        RECT 0.690 605.840 1299.070 609.360 ;
      LAYER Nwell ;
        RECT 0.690 601.520 1299.070 605.840 ;
      LAYER Pwell ;
        RECT 0.690 598.000 1299.070 601.520 ;
      LAYER Nwell ;
        RECT 0.690 593.680 1299.070 598.000 ;
      LAYER Pwell ;
        RECT 0.690 590.160 1299.070 593.680 ;
      LAYER Nwell ;
        RECT 0.690 585.840 1299.070 590.160 ;
      LAYER Pwell ;
        RECT 0.690 582.320 1299.070 585.840 ;
      LAYER Nwell ;
        RECT 0.690 578.000 1299.070 582.320 ;
      LAYER Pwell ;
        RECT 0.690 574.480 1299.070 578.000 ;
      LAYER Nwell ;
        RECT 0.690 570.160 1299.070 574.480 ;
      LAYER Pwell ;
        RECT 0.690 566.640 1299.070 570.160 ;
      LAYER Nwell ;
        RECT 0.690 562.320 1299.070 566.640 ;
      LAYER Pwell ;
        RECT 0.690 558.800 1299.070 562.320 ;
      LAYER Nwell ;
        RECT 0.690 554.480 1299.070 558.800 ;
      LAYER Pwell ;
        RECT 0.690 550.960 1299.070 554.480 ;
      LAYER Nwell ;
        RECT 0.690 546.640 1299.070 550.960 ;
      LAYER Pwell ;
        RECT 0.690 543.120 1299.070 546.640 ;
      LAYER Nwell ;
        RECT 0.690 538.800 1299.070 543.120 ;
      LAYER Pwell ;
        RECT 0.690 535.280 1299.070 538.800 ;
      LAYER Nwell ;
        RECT 0.690 530.960 1299.070 535.280 ;
      LAYER Pwell ;
        RECT 0.690 527.440 1299.070 530.960 ;
      LAYER Nwell ;
        RECT 0.690 523.120 1299.070 527.440 ;
      LAYER Pwell ;
        RECT 0.690 519.600 1299.070 523.120 ;
      LAYER Nwell ;
        RECT 0.690 515.280 1299.070 519.600 ;
      LAYER Pwell ;
        RECT 0.690 511.760 1299.070 515.280 ;
      LAYER Nwell ;
        RECT 0.690 507.440 1299.070 511.760 ;
      LAYER Pwell ;
        RECT 0.690 503.920 1299.070 507.440 ;
      LAYER Nwell ;
        RECT 0.690 499.600 1299.070 503.920 ;
      LAYER Pwell ;
        RECT 0.690 496.080 1299.070 499.600 ;
      LAYER Nwell ;
        RECT 0.690 491.760 1299.070 496.080 ;
      LAYER Pwell ;
        RECT 0.690 488.240 1299.070 491.760 ;
      LAYER Nwell ;
        RECT 0.690 483.920 1299.070 488.240 ;
      LAYER Pwell ;
        RECT 0.690 480.400 1299.070 483.920 ;
      LAYER Nwell ;
        RECT 0.690 476.080 1299.070 480.400 ;
      LAYER Pwell ;
        RECT 0.690 472.560 1299.070 476.080 ;
      LAYER Nwell ;
        RECT 0.690 468.240 1299.070 472.560 ;
      LAYER Pwell ;
        RECT 0.690 464.720 1299.070 468.240 ;
      LAYER Nwell ;
        RECT 0.690 460.400 1299.070 464.720 ;
      LAYER Pwell ;
        RECT 0.690 456.880 1299.070 460.400 ;
      LAYER Nwell ;
        RECT 0.690 452.560 1299.070 456.880 ;
      LAYER Pwell ;
        RECT 0.690 449.040 1299.070 452.560 ;
      LAYER Nwell ;
        RECT 0.690 444.720 1299.070 449.040 ;
      LAYER Pwell ;
        RECT 0.690 441.200 1299.070 444.720 ;
      LAYER Nwell ;
        RECT 0.690 436.880 1299.070 441.200 ;
      LAYER Pwell ;
        RECT 0.690 433.360 1299.070 436.880 ;
      LAYER Nwell ;
        RECT 0.690 429.040 1299.070 433.360 ;
      LAYER Pwell ;
        RECT 0.690 425.520 1299.070 429.040 ;
      LAYER Nwell ;
        RECT 0.690 421.200 1299.070 425.520 ;
      LAYER Pwell ;
        RECT 0.690 417.680 1299.070 421.200 ;
      LAYER Nwell ;
        RECT 0.690 413.360 1299.070 417.680 ;
      LAYER Pwell ;
        RECT 0.690 409.840 1299.070 413.360 ;
      LAYER Nwell ;
        RECT 0.690 405.520 1299.070 409.840 ;
      LAYER Pwell ;
        RECT 0.690 402.000 1299.070 405.520 ;
      LAYER Nwell ;
        RECT 0.690 397.680 1299.070 402.000 ;
      LAYER Pwell ;
        RECT 0.690 394.160 1299.070 397.680 ;
      LAYER Nwell ;
        RECT 0.690 389.840 1299.070 394.160 ;
      LAYER Pwell ;
        RECT 0.690 386.320 1299.070 389.840 ;
      LAYER Nwell ;
        RECT 0.690 382.000 1299.070 386.320 ;
      LAYER Pwell ;
        RECT 0.690 378.480 1299.070 382.000 ;
      LAYER Nwell ;
        RECT 0.690 374.160 1299.070 378.480 ;
      LAYER Pwell ;
        RECT 0.690 370.640 1299.070 374.160 ;
      LAYER Nwell ;
        RECT 0.690 366.320 1299.070 370.640 ;
      LAYER Pwell ;
        RECT 0.690 362.800 1299.070 366.320 ;
      LAYER Nwell ;
        RECT 0.690 358.480 1299.070 362.800 ;
      LAYER Pwell ;
        RECT 0.690 354.960 1299.070 358.480 ;
      LAYER Nwell ;
        RECT 0.690 350.640 1299.070 354.960 ;
      LAYER Pwell ;
        RECT 0.690 347.120 1299.070 350.640 ;
      LAYER Nwell ;
        RECT 0.690 342.800 1299.070 347.120 ;
      LAYER Pwell ;
        RECT 0.690 339.280 1299.070 342.800 ;
      LAYER Nwell ;
        RECT 0.690 334.960 1299.070 339.280 ;
      LAYER Pwell ;
        RECT 0.690 331.440 1299.070 334.960 ;
      LAYER Nwell ;
        RECT 0.690 327.120 1299.070 331.440 ;
      LAYER Pwell ;
        RECT 0.690 323.600 1299.070 327.120 ;
      LAYER Nwell ;
        RECT 0.690 319.280 1299.070 323.600 ;
      LAYER Pwell ;
        RECT 0.690 315.760 1299.070 319.280 ;
      LAYER Nwell ;
        RECT 0.690 311.440 1299.070 315.760 ;
      LAYER Pwell ;
        RECT 0.690 307.920 1299.070 311.440 ;
      LAYER Nwell ;
        RECT 0.690 303.600 1299.070 307.920 ;
      LAYER Pwell ;
        RECT 0.690 300.080 1299.070 303.600 ;
      LAYER Nwell ;
        RECT 0.690 295.760 1299.070 300.080 ;
      LAYER Pwell ;
        RECT 0.690 292.240 1299.070 295.760 ;
      LAYER Nwell ;
        RECT 0.690 287.920 1299.070 292.240 ;
      LAYER Pwell ;
        RECT 0.690 284.400 1299.070 287.920 ;
      LAYER Nwell ;
        RECT 0.690 280.080 1299.070 284.400 ;
      LAYER Pwell ;
        RECT 0.690 276.560 1299.070 280.080 ;
      LAYER Nwell ;
        RECT 0.690 272.240 1299.070 276.560 ;
      LAYER Pwell ;
        RECT 0.690 268.720 1299.070 272.240 ;
      LAYER Nwell ;
        RECT 0.690 264.400 1299.070 268.720 ;
      LAYER Pwell ;
        RECT 0.690 260.880 1299.070 264.400 ;
      LAYER Nwell ;
        RECT 0.690 256.560 1299.070 260.880 ;
      LAYER Pwell ;
        RECT 0.690 253.040 1299.070 256.560 ;
      LAYER Nwell ;
        RECT 0.690 248.720 1299.070 253.040 ;
      LAYER Pwell ;
        RECT 0.690 245.200 1299.070 248.720 ;
      LAYER Nwell ;
        RECT 0.690 240.880 1299.070 245.200 ;
      LAYER Pwell ;
        RECT 0.690 237.360 1299.070 240.880 ;
      LAYER Nwell ;
        RECT 0.690 233.040 1299.070 237.360 ;
      LAYER Pwell ;
        RECT 0.690 229.520 1299.070 233.040 ;
      LAYER Nwell ;
        RECT 0.690 225.200 1299.070 229.520 ;
      LAYER Pwell ;
        RECT 0.690 221.680 1299.070 225.200 ;
      LAYER Nwell ;
        RECT 0.690 217.360 1299.070 221.680 ;
      LAYER Pwell ;
        RECT 0.690 213.840 1299.070 217.360 ;
      LAYER Nwell ;
        RECT 0.690 209.520 1299.070 213.840 ;
      LAYER Pwell ;
        RECT 0.690 206.000 1299.070 209.520 ;
      LAYER Nwell ;
        RECT 0.690 201.680 1299.070 206.000 ;
      LAYER Pwell ;
        RECT 0.690 198.160 1299.070 201.680 ;
      LAYER Nwell ;
        RECT 0.690 193.840 1299.070 198.160 ;
      LAYER Pwell ;
        RECT 0.690 190.320 1299.070 193.840 ;
      LAYER Nwell ;
        RECT 0.690 186.000 1299.070 190.320 ;
      LAYER Pwell ;
        RECT 0.690 182.480 1299.070 186.000 ;
      LAYER Nwell ;
        RECT 0.690 178.160 1299.070 182.480 ;
      LAYER Pwell ;
        RECT 0.690 174.640 1299.070 178.160 ;
      LAYER Nwell ;
        RECT 0.690 170.320 1299.070 174.640 ;
      LAYER Pwell ;
        RECT 0.690 166.800 1299.070 170.320 ;
      LAYER Nwell ;
        RECT 0.690 162.480 1299.070 166.800 ;
      LAYER Pwell ;
        RECT 0.690 158.960 1299.070 162.480 ;
      LAYER Nwell ;
        RECT 0.690 154.640 1299.070 158.960 ;
      LAYER Pwell ;
        RECT 0.690 151.120 1299.070 154.640 ;
      LAYER Nwell ;
        RECT 0.690 146.800 1299.070 151.120 ;
      LAYER Pwell ;
        RECT 0.690 143.280 1299.070 146.800 ;
      LAYER Nwell ;
        RECT 0.690 138.960 1299.070 143.280 ;
      LAYER Pwell ;
        RECT 0.690 135.440 1299.070 138.960 ;
      LAYER Nwell ;
        RECT 0.690 131.120 1299.070 135.440 ;
      LAYER Pwell ;
        RECT 0.690 127.600 1299.070 131.120 ;
      LAYER Nwell ;
        RECT 0.690 123.280 1299.070 127.600 ;
      LAYER Pwell ;
        RECT 0.690 119.760 1299.070 123.280 ;
      LAYER Nwell ;
        RECT 0.690 115.440 1299.070 119.760 ;
      LAYER Pwell ;
        RECT 0.690 111.920 1299.070 115.440 ;
      LAYER Nwell ;
        RECT 0.690 107.600 1299.070 111.920 ;
      LAYER Pwell ;
        RECT 0.690 104.080 1299.070 107.600 ;
      LAYER Nwell ;
        RECT 0.690 99.760 1299.070 104.080 ;
      LAYER Pwell ;
        RECT 0.690 96.240 1299.070 99.760 ;
      LAYER Nwell ;
        RECT 0.690 91.920 1299.070 96.240 ;
      LAYER Pwell ;
        RECT 0.690 88.400 1299.070 91.920 ;
      LAYER Nwell ;
        RECT 0.690 84.080 1299.070 88.400 ;
      LAYER Pwell ;
        RECT 0.690 80.560 1299.070 84.080 ;
      LAYER Nwell ;
        RECT 0.690 76.240 1299.070 80.560 ;
      LAYER Pwell ;
        RECT 0.690 72.720 1299.070 76.240 ;
      LAYER Nwell ;
        RECT 0.690 68.400 1299.070 72.720 ;
      LAYER Pwell ;
        RECT 0.690 64.880 1299.070 68.400 ;
      LAYER Nwell ;
        RECT 0.690 60.560 1299.070 64.880 ;
      LAYER Pwell ;
        RECT 0.690 57.040 1299.070 60.560 ;
      LAYER Nwell ;
        RECT 0.690 52.720 1299.070 57.040 ;
      LAYER Pwell ;
        RECT 0.690 49.200 1299.070 52.720 ;
      LAYER Nwell ;
        RECT 0.690 44.880 1299.070 49.200 ;
      LAYER Pwell ;
        RECT 0.690 41.360 1299.070 44.880 ;
      LAYER Nwell ;
        RECT 0.690 37.040 1299.070 41.360 ;
      LAYER Pwell ;
        RECT 0.690 33.520 1299.070 37.040 ;
      LAYER Nwell ;
        RECT 0.690 29.200 1299.070 33.520 ;
      LAYER Pwell ;
        RECT 0.690 25.680 1299.070 29.200 ;
      LAYER Nwell ;
        RECT 0.690 21.360 1299.070 25.680 ;
      LAYER Pwell ;
        RECT 0.690 17.840 1299.070 21.360 ;
      LAYER Nwell ;
        RECT 0.690 13.520 1299.070 17.840 ;
      LAYER Pwell ;
        RECT 0.690 10.000 1299.070 13.520 ;
      LAYER Nwell ;
        RECT 0.690 5.680 1299.070 10.000 ;
      LAYER Pwell ;
        RECT 0.690 3.490 1299.070 5.680 ;
      LAYER Metal1 ;
        RECT 1.120 3.620 1298.640 995.980 ;
      LAYER Metal2 ;
        RECT 15.220 999.140 547.380 999.860 ;
        RECT 548.540 999.140 549.620 999.860 ;
        RECT 551.900 999.140 554.100 999.860 ;
        RECT 555.260 999.140 572.020 999.860 ;
        RECT 573.180 999.140 574.260 999.860 ;
        RECT 575.420 999.140 577.620 999.860 ;
        RECT 578.780 999.140 591.060 999.860 ;
        RECT 592.220 999.140 593.300 999.860 ;
        RECT 594.460 999.140 598.900 999.860 ;
        RECT 600.060 999.140 612.340 999.860 ;
        RECT 613.500 999.140 615.700 999.860 ;
        RECT 617.980 999.140 625.780 999.860 ;
        RECT 626.940 999.140 632.500 999.860 ;
        RECT 634.780 999.140 656.020 999.860 ;
        RECT 659.420 999.140 667.220 999.860 ;
        RECT 668.380 999.140 670.580 999.860 ;
        RECT 677.340 999.140 678.420 999.860 ;
        RECT 685.180 999.140 686.260 999.860 ;
        RECT 689.660 999.140 691.860 999.860 ;
        RECT 696.380 999.140 700.820 999.860 ;
        RECT 701.980 999.140 705.300 999.860 ;
        RECT 717.660 999.140 720.980 999.860 ;
        RECT 731.100 999.140 737.780 999.860 ;
        RECT 741.180 999.140 743.380 999.860 ;
        RECT 744.540 999.140 750.100 999.860 ;
        RECT 753.500 999.140 754.580 999.860 ;
        RECT 755.740 999.140 1294.660 999.860 ;
        RECT 15.220 0.860 1294.660 999.140 ;
        RECT 15.220 0.140 531.700 0.860 ;
        RECT 532.860 0.140 545.140 0.860 ;
        RECT 546.300 0.140 548.500 0.860 ;
        RECT 555.260 0.140 556.340 0.860 ;
        RECT 557.500 0.140 559.700 0.860 ;
        RECT 560.860 0.140 565.300 0.860 ;
        RECT 566.460 0.140 568.660 0.860 ;
        RECT 572.060 0.140 573.140 0.860 ;
        RECT 576.540 0.140 583.220 0.860 ;
        RECT 584.380 0.140 585.460 0.860 ;
        RECT 587.740 0.140 594.420 0.860 ;
        RECT 595.580 0.140 604.500 0.860 ;
        RECT 605.660 0.140 607.860 0.860 ;
        RECT 624.700 0.140 631.380 0.860 ;
        RECT 632.540 0.140 635.860 0.860 ;
        RECT 637.020 0.140 640.340 0.860 ;
        RECT 641.500 0.140 645.940 0.860 ;
        RECT 647.100 0.140 651.540 0.860 ;
        RECT 652.700 0.140 660.500 0.860 ;
        RECT 661.660 0.140 662.740 0.860 ;
        RECT 663.900 0.140 671.700 0.860 ;
        RECT 672.860 0.140 688.500 0.860 ;
        RECT 689.660 0.140 1294.660 0.860 ;
      LAYER Metal3 ;
        RECT 15.170 0.140 1294.710 999.460 ;
      LAYER Metal4 ;
        RECT 551.740 0.090 614.640 995.030 ;
        RECT 620.240 0.090 620.640 995.030 ;
        RECT 626.240 0.090 689.640 995.030 ;
        RECT 695.240 0.090 695.640 995.030 ;
        RECT 701.240 0.090 732.900 995.030 ;
      LAYER Metal5 ;
        RECT 681.580 974.030 706.100 974.470 ;
  END
END butterfold_top_control
END LIBRARY

